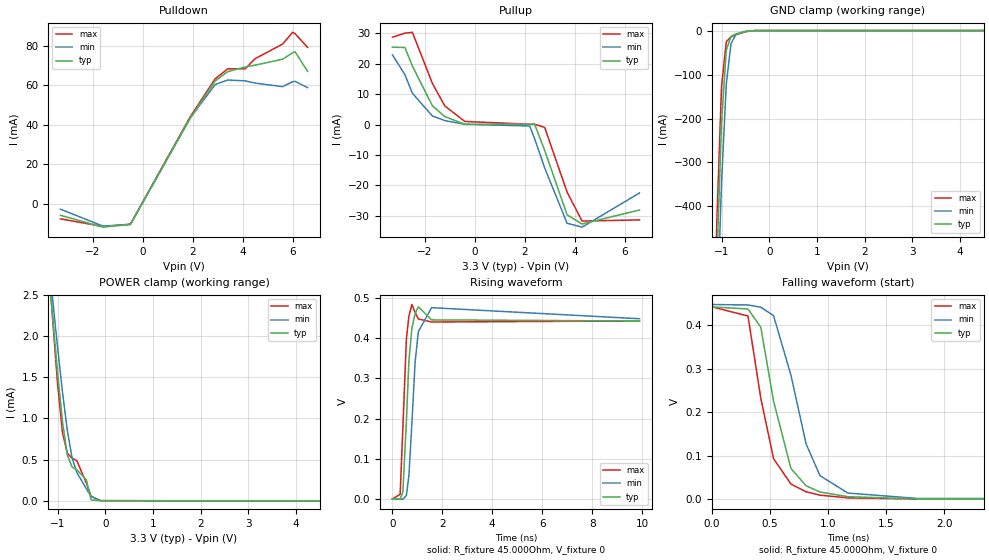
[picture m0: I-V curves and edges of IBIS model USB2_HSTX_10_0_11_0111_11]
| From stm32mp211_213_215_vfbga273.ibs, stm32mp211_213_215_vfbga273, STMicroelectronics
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[Model] USB2_HSTX_10_0_11_0111_11
Model_type   Output
Polarity   Non-Inverting
Enable   Active-High
C_comp   8.036pF   7.631pF   8.569pF
Vmeas = 200.000mV
Vref = 200.000mV
Rref = 45Ohms
Cref = 0pF
[Model Spec]
Vmeas   200.000mV   200.000mV   200.000mV
Vref   200.000mV   200.000mV   200.000mV
| This model is not intended for timing simulations.
| Warnings about Cref, Vref & Rref can be ignored
[Temperature Range]   25.000   125.000   -40.000
[Voltage Range]   3.300V   3.070V   3.630V
[GND Clamp Reference]   0.00V   0.00V   0.00V
[Pulldown Reference]   0.00V   0.00V   0.00V
[POWER Clamp Reference]   3.300V   3.070V   3.630V
[Pullup Reference]   3.300V   3.070V   3.630V
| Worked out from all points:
|   slope of the pulldown table from 0 to 0.495 V, typ, clamps not added: 42.6 ohm
|   GND clamp passes 1 mA (typ) near -0.43 V on its own axis
|   POWER clamp passes 1 mA (typ) near -0.91 V on its own axis
|   rising waveform, R_fixture 45.000Ohm, V_fixture 0: 20-80 % time 177ps typ, 237ps min, 137ps max; typ from 0 V to 0.442 V
|   falling waveform, R_fixture 45.000Ohm, V_fixture 0: 20-80 % time 196ps typ, 242ps min, 176ps max; typ from 0.442 V to 0 V
[GND Clamp]
-3.3V     -11.02A    -10.62A    -11.32A
-1.2V     -931.6mA   -1.049A    -855.7mA
-1.1V     -533.1mA   -671.7mA   -440.2mA
-1V       -209.4mA   -347mA     -127.3mA
-900mV    -44.44mA   -121.7mA   -25.6mA
-800mV    -13.15mA   -29.48mA   -14.15mA
-700mV    -7.742mA   -9.125mA   -9.769mA
-500mV    -2.127mA   -1.981mA   -2.894mA
-300mV    -19.29uA   -62.22uA   -13.76uA
6.6V      10.37uA    26.58uA    21.05uA
[Power Clamp]
-3.3V     3.206A     2.175A     4.855A
-1.2V     2.88mA     3.008mA    2.969mA
-1.1V     2.195mA    2.419mA    2.156mA
-1V       1.545mA    1.852mA    1.406mA
-900mV    967.9uA    1.325mA    831.4uA
-800mV    558.5uA    864.5uA    580.3uA
-700mV    412uA      525.9uA    517uA
-600mV    376.6uA    345uA      488.5uA
-400mV    254.2uA    146.6uA    216.8uA
-300mV    11.21uA    52.88uA    53.51uA
-100mV    94.92nA    985.3nA    361.1nA
6.6V      -3.569uA   -5.179uA   -2.984uA
[Pulldown]
-3.3V     -5.671mA   -2.581mA   -7.449mA
-1.6V     -11.64mA   -11.09mA   -11.31mA
-500mV    -10.25mA   -10.32mA   -10.1mA
1.9V      43.42mA    43.46mA    44.13mA
2.9V      62.15mA    60.37mA    63.26mA
3.4V      66.87mA    62.63mA    68.29mA
4.1V      69.19mA    62.19mA    68.26mA
4.5V      70.11mA    61.06mA    73.4mA
5.6V      73.12mA    59.29mA    80.76mA
6V        76.33mA    61.76mA    86.69mA
6.1V      76.87mA    61.94mA    85.99mA
6.6V      66.99mA    58.79mA    79.1mA
[Pullup]
-3.3V     25.41mA    22.88mA    28.68mA
-2.8V     25.3mA     16.38mA    30mA
-2.5V     19.22mA    10.28mA    30.28mA
-1.7V     6.185mA    2.829mA    13.54mA
-1.2V     2.602mA    1.31mA     6.111mA
-400mV    111.7uA    77.66uA    1.021mA
2.2V      68.59uA    -465.1uA   104.8uA
2.4V      56.18uA    -4.685mA   90.82uA
2.8V      -8.459mA   -14.22mA   -920uA
3.7V      -29.65mA   -32.41mA   -22.19mA
4.3V      -32.64mA   -33.68mA   -31.68mA
6.6V      -28.04mA   -22.46mA   -31.3mA
[Ramp]
R_load=45.000Ohm
dV/dt_r   633.005mV/980.000ps  601.223mV/995.000ps  686.718mV/915.000ps
dV/dt_f   635.188mV/225.000ps  604.118mV/285.000ps  688.534mV/210.000ps
[Rising waveform]
R_fixture=45.000Ohm
V_fixture=0
0s        452.3nV    3.135uV    468.1nV
310ps     -557.4uV   -364.4uV   12.02mV
420ps     18.8mV     -644.1uV   179.9mV
560ps     193.8mV    8.956mV    398.1mV
660ps     342.6mV    57.92mV    454.4mV
780ps     424.4mV    188.7mV    483.5mV
910ps     461.2mV    340.9mV    463.7mV
1.04ns    477.7mV    416.3mV    447.5mV
1.57ns    445.3mV    475.6mV    440mV
9.9ns     442.4mV    448.1mV    442.6mV
[Falling waveform]
R_fixture=45.000Ohm
V_fixture=0
0s        441.9mV    447.5mV    442.1mV
310ps     437.2mV    446.4mV    421mV
420ps     395.5mV    441.3mV    232.7mV
530ps     225.9mV    422mV      93.46mV
680ps     70.69mV    285.1mV    34.97mV
810ps     31.17mV    127.6mV    17.35mV
930ps     16.79mV    54.32mV    9.567mV
1.17ns    6.065mV    14.44mV    3.331mV
1.77ns    897.4uV    2.036mV    703uV
9.9ns     14.42uV    31.18uV    4.706uV
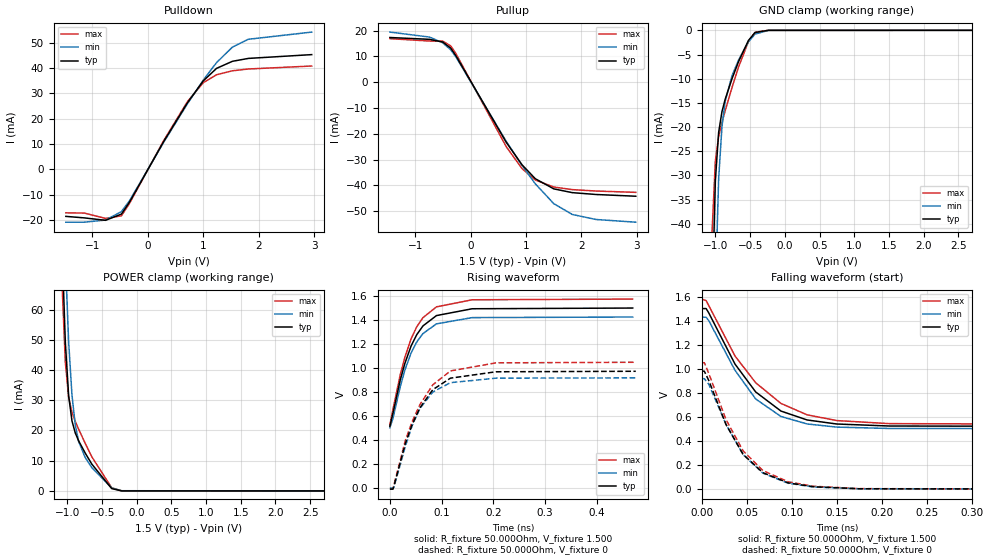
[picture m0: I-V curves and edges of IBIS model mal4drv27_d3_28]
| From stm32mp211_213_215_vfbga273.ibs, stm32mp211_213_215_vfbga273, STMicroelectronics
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[Model] mal4drv27_d3_28
Model_type   I/O
Polarity   Non-Inverting
Enable   Active-High
C_comp   1.653pF   1.649pF   1.658pF
C_comp_pullup   821.240fF   815.174fF   828.427fF
C_comp_pulldown 737.945fF   733.914fF   744.436fF
Vinh = 885.000mV
Vinl = 615.000mV
Vmeas = 750.000mV
Vref = 750.000mV
Rref = 50Ohms
Cref = 0pF
[Model Spec]
Vinh   885.000mV   848.000mV   923.000mV
Vinl   615.000mV   578.000mV   653.000mV
Vmeas   750.000mV   713.000mV   788.000mV
Vref   750.000mV   713.000mV   788.000mV
D_overshoot_ampl_h 0.4 NA   NA
D_overshoot_ampl_l 0.4 NA   NA
D_overshoot_area_l 100.000m NA   NA
D_overshoot_area_h 100.000m NA   NA
[Receiver Thresholds]
Vth = 750.000mV
Vth_min = 713.000mV
Vth_max = 788.000mV
Vinh_ac = 135.000mV
Vinh_dc = 100.000mV
Vinl_ac = -135.000mV
Vinl_dc = -100.000mV
Tslew_ac = 5.000ns
Threshold_sensitivity = 0.5
Reference_supply Pullup_ref
[Temperature Range]   25.000   125.000   -40.000
[Voltage Range]   1.500V   1.425V   1.575V
[GND Clamp Reference]   0.00V   0.00V   0.00V
[C Comp Corner]
| variable   typ   min   max
C_comp 1.658pF   1.653pF   1.649pF
C_comp_pullup 821.240fF   828.427fF   815.174fF
C_comp_pulldown 733.914fF   744.436fF   737.945fF
[Pulldown Reference]   0.00V   0.00V   0.00V
[POWER Clamp Reference]   1.500V   1.425V   1.575V
[Pullup Reference]   1.500V   1.425V   1.575V
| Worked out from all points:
|   slope of the pulldown table from 0 to 0.225 V, typ, clamps not added: 26 ohm
|   slope of the pullup table from 0 to 0.225 V, typ, clamps not added: 26.5 ohm
|   GND clamp passes 1 mA (typ) near -0.47 V on its own axis
|   POWER clamp passes 1 mA (typ) near -0.37 V on its own axis
|   rising waveform, R_fixture 50.000Ohm, V_fixture 1.500: 20-80 % time 45.5ps typ, 43.8ps min, 45.4ps max; typ from 0.513 V to 1.5 V
|   rising waveform, R_fixture 50.000Ohm, V_fixture 0: 20-80 % time 56ps typ, 49ps min, 60.9ps max; typ from -0.013 V to 0.972 V
|   falling waveform, R_fixture 50.000Ohm, V_fixture 1.500: 20-80 % time 54.5ps typ, 49.6ps min, 62.5ps max; typ from 1.5 V to 0.521 V
|   falling waveform, R_fixture 50.000Ohm, V_fixture 0: 20-80 % time 43.5ps typ, 42.5ps min, 45.2ps max; typ from 0.981 V to 0 V
[GND Clamp]
-1.48V    -1.356A    -1.372A    -1.368A
-1.05V    -57.52mA   -98.82mA   -41.99mA
-1.002V   -31.12mA   -53.93mA   -27.05mA
-954.6mV  -21.13mA   -30.8mA    -21.99mA
-906.8mV  -16.83mA   -19.93mA   -19.06mA
-859.1mV  -14.2mA    -14.62mA   -16.56mA
-763.6mV  -10.09mA   -9.457mA   -11.91mA
-668.2mV  -6.482mA   -6.16mA    -7.611mA
-525mV    -2.097mA   -2.366mA   -2.333mA
-429.5mV  -449.8uA   -771.1uA   -394uA
-238.6mV  -1.709uA   -14.74uA   -370nA
2.959V    53.06nA    707.1nA    76.78nA
[Power Clamp]
-1.459V   570.2mA    591.8mA    567.2mA
-1.077V   80.71mA    114.2mA    68.27mA
-1.03V    49.21mA    76.71mA    42.66mA
-981.8mV  31.4mA     49.26mA    30.9mA
-934.1mV  23.16mA    31.72mA    25.95mA
-886.4mV  19.16mA    21.79mA    22.98mA
-838.6mV  16.6mA     16.39mA    20.46mA
-743.2mV  12.52mA    11.03mA    15.74mA
-647.7mV  8.857mA    7.696mA    11.27mA
-361.4mV  773.2uA    986uA      1.034mA
-218.2mV  12.39uA    63.5uA     9.952uA
2.98V     -55.08nA   -1.144uA   -55.82nA
[Pulldown]
-1.48V    -18.6mA    -20.9mA    -17.2mA
-1.145V   -19.2mA    -20.9mA    -17.3mA
-763.6mV  -20.16mA   -20.06mA   -19.41mA
-477.3mV  -17.72mA   -16.73mA   -18.39mA
-334.1mV  -13.11mA   -12.56mA   -13.62mA
286.4mV   10.96mA    10.65mA    11.33mA
715.9mV   26.29mA    25.91mA    26.75mA
1.002V    34.94mA    35.26mA    34.24mA
1.241V    39.87mA    42.14mA    37.35mA
1.527V    42.66mA    48.26mA    38.91mA
1.814V    43.8mA     51.36mA    39.62mA
2.959V    45.3mA     54.2mA     40.8mA
[Pullup]
-1.459V   17.3mA     19.4mA     16.86mA
-743.2mV  16.59mA    17.47mA    15.93mA
-504.6mV  15.55mA    15.25mA    15.9mA
-361.4mV  13.21mA    12.54mA    14.08mA
-265.9mV  10.19mA    9.733mA    11.02mA
640.9mV   -23.29mA   -22.91mA   -24.99mA
927.3mV   -32.04mA   -32.32mA   -33.51mA
1.166V    -37.41mA   -39.38mA   -37.92mA
1.5V      -41.35mA   -47.08mA   -40.64mA
1.834V    -42.81mA   -51.27mA   -41.64mA
2.264V    -43.53mA   -53.22mA   -42.19mA
2.98V     -44.2mA    -54.26mA   -42.7mA
[Ramp]
R_load=50.000Ohm
dV/dt_r   585.090mV/51.500ps  551.819mV/47.000ps  624.990mV/54.000ps
dV/dt_f   585.090mV/50.000ps  551.819mV/47.000ps  624.990mV/55.000ps
[Rising waveform]
R_fixture=50.000Ohm
V_fixture=1.500
V_fixture_min=1.425
V_fixture_max=1.575
0s        512.6mV    499.1mV    523.9mV
6ps       621.6mV    578mV      654.3mV
20ps      897.6mV    841mV      941.6mV
29ps      1.038V     982.2mV    1.089V
41ps      1.183V     1.125V     1.243V
52ps      1.278V     1.217V     1.344V
64ps      1.351V     1.287V     1.42V
90ps      1.437V     1.368V     1.51V
159ps     1.494V     1.42V      1.569V
469ps     1.5V       1.425V     1.575V
[Rising waveform]
R_fixture=50.000Ohm
V_fixture=0
0s        -13.22mV   -4.701mV   -7.609mV
6ps       -13.22mV   -4.701mV   -7.609mV
8ps       15.04mV    5.879mV    25.27mV
30ps      369.4mV    345.7mV    395.1mV
43ps      526.2mV    517.1mV    550.7mV
58ps      666mV      660mV      693.2mV
83ps      818.3mV    798.6mV    858.8mV
117ps     914.2mV    876.6mV    974.5mV
205ps     967.5mV    914.2mV    1.042V
475ps     971.7mV    916.7mV    1.047V
[Falling waveform]
R_fixture=50.000Ohm
V_fixture=1.500
V_fixture_min=1.425
V_fixture_max=1.575
0s        1.501V     1.429V     1.58V
5ps       1.501V     1.429V     1.567V
8ps       1.464V     1.4V       1.525V
37ps      1.04V      988.5mV    1.107V
60ps      807.7mV    749.2mV    884.4mV
88ps      649.1mV    604.1mV    712.5mV
117ps     575.2mV    542mV      617.9mV
150ps     541.5mV    515.8mV    570mV
208ps     524.9mV    504.4mV    544.7mV
474ps     521.4mV    502.3mV    538.7mV
[Falling waveform]
R_fixture=50.000Ohm
V_fixture=0
0s        980.7mV    918.2mV    1.051V
3ps       980.7mV    918.2mV    1.051V
8ps       902.3mV    871.3mV    960.9mV
27ps      537.9mV    540mV      579.2mV
46ps      289.4mV    287.1mV    318.7mV
68ps      136.8mV    133mV      154.4mV
96ps      52.35mV    49.03mV    61.06mV
124ps     20.03mV    18.04mV    24.06mV
175ps     3.445mV    3.002mV    4.366mV
472ps     2.087uV    7.008uV    2.036uV
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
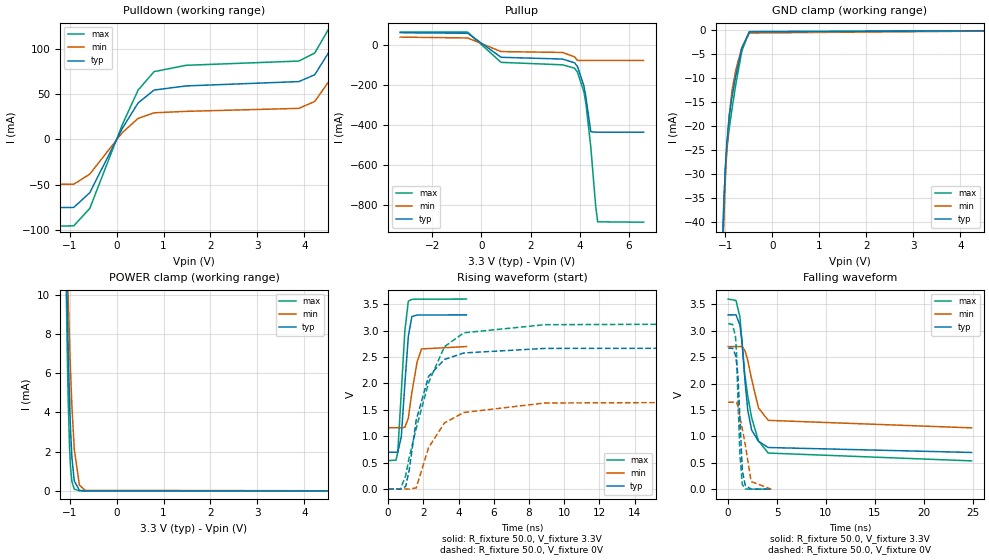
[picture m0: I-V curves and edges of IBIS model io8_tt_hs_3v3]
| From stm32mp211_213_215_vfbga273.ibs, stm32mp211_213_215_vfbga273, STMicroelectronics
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[Model]   io8_tt_hs_3v3
Model_type I/O
Polarity   Non-Inverting
Enable   Active-Low
| CAP_THRESHOLD on pad IOTT is "UDTCAPC" :
| Rising=30.0% of vddiov33m   Falling=70.0% of vddiov33m
| C_comp min and max val. don't necessarily correlate with the min and max pvt
| but are the smallest and greatest pad capacitance found.
| var   typ   min   max
C_comp   1.01876pF  1.01072pF  1.02145pF
|C_comp_pullup   495.66000fF  479.35500fF  510.70500fF
|C_comp_pulldown   523.10000fF  531.36929fF  510.74000fF
Vinl = 1.35V
Vinh = 1.8V
Vmeas = 1.65V   | Reference voltage for timing measurements
Cref  = 50.0pF   | Timing specification test load capacitance value
Rref  = 1.0MOhm   | Timing specification test load resistance value
Vref  = 1.815V   | Timing specification test load voltage
[Model Spec]
| TIME_THRESHOLD on pin ZIV08M is "CMOS" :
| Rising=50.0% of vddv08m   Falling=50.0% of vddv08m
Vinl 1.08570V 868.70000mV 1.21270V
Vinh 1.55630V 1.26230V 1.70930V
| variable   typ   min   max
[Temperature Range] 25.0 125.0 -40.0
| variable   typ   min   max
[Voltage Range] 3.3V 2.7V 3.6V
| variable   typ   min   max
[POWER Clamp Reference] 3.3V 2.7V 3.6V
| variable   typ   min   max
[GND Clamp Reference] 0V 0V 0V
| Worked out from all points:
|   slope of the pulldown table from 0 to 0.495 V, typ, clamps not added: 11.6 ohm
|   slope of the pullup table from 0 to 0.495 V, typ, clamps not added: 10.9 ohm
|   GND clamp passes 1 mA (typ) near -0.55 V on its own axis
|   POWER clamp passes 1 mA (typ) near -0.92 V on its own axis
|   rising waveform, R_fixture 50.0, V_fixture 3.3V: 20-80 % time 324ps typ, 432ps min, 308ps max; typ from 0.695 V to 3.3 V
|   falling waveform, R_fixture 50.0, V_fixture 3.3V: 20-80 % time 837ps typ, 1.2ns min, 1.33ns max; typ from 3.3 V to 0.695 V
|   rising waveform, R_fixture 50.0, V_fixture 0V: 20-80 % time 1.04ns typ, 1.55ns min, 1.64ns max; typ from 0 V to 2.67 V
|   falling waveform, R_fixture 50.0, V_fixture 0V: 20-80 % time 373ps typ, 836ps min, 339ps max; typ from 2.67 V to 0 V
[POWER Clamp]
-3.3V     1.353A     318.4mA    2.015A
-1.07V    12.07mA    13.62mA    10.38mA
-1.06V    10.79mA    12.68mA    8.745mA
-1.05V    9.571mA    11.76mA    7.253mA
-1.03V    7.341mA    9.999mA    4.748mA
-1V       4.588mA    7.595mA    2.215mA
-980mV    3.183mA    6.171mA    1.238mA
-950mV    1.704mA    4.337mA    481.8uA
-900mV    515.5uA    2.141mA    93.34uA
-790mV    29.45uA    301.7uA    4.884uA
-670mV    1.871uA    28.97uA    2.19uA
6.6V      0A         0A         0A
[GND Clamp]
-3.3V     -3.772A    -3.743A    -3.788A
-1.05V    -42.34mA   -45.44mA   -41.2mA
-1.04V    -38.9mA    -42mA      -37.88mA
-1.03V    -35.84mA   -38.88mA   -35.06mA
-1V       -28.57mA   -31.07mA   -28.88mA
-970mV    -23.48mA   -25.09mA   -24.97mA
-920mV    -18.07mA   -17.99mA   -20.63mA
-860mV    -13.91mA   -12.68mA   -16.46mA
-780mV    -9.536mA   -8.318mA   -11.38mA
-650mV    -3.744mA   -3.567mA   -4.327mA
-490mV    -324.2uA   -555.2uA   -259.7uA
6.6V      214nA      4.276uA    223.3nA
| variable   typ   min   max
[Pullup Reference] 3.3V 2.7V 3.6V
| variable   typ   min   max
[Pulldown Reference] 0V 0V 0V
[Pullup]
-3.3V     63.52mA    41.46mA    66.64mA
-560mV    60.73mA    37.23mA    66.64mA
800mV     -59.67mA   -31.11mA   -85.07mA
3.3V      -68.5mA    -35.37mA   -97.42mA
3.79V     -87.42mA   -57.42mA   -114.2mA
3.91V     -106.3mA   -75.62mA   -134.5mA
4.17V     -203.5mA   -75.62mA   -232.9mA
4.25V     -258.5mA   -75.62mA   -290.9mA
4.45V     -432.8mA   -75.62mA   -509.3mA
4.65V     -435.1mA   -75.62mA   -808.5mA
4.73V     -435.1mA   -75.62mA   -884.5mA
6.6V      -435.1mA   -75.62mA   -886.3mA
[Pulldown]
-3.3V     -76.59mA   -50.19mA   -97.29mA
-910mV    -75.37mA   -49.66mA   -95.8mA
-570mV    -59.08mA   -38.48mA   -76.52mA
120mV     12mA       7.376mA    15.98mA
460mV     40.46mA    23.32mA    54.73mA
800mV     54.75mA    29.51mA    75.15mA
1.48V     59.3mA     31.12mA    82.16mA
3.88V     64.12mA    34.44mA    86.87mA
4.22V     71.69mA    42.06mA    95.8mA
4.56V     100mA      67.27mA    126.4mA
4.9V      185.2mA    140.4mA    220.4mA
6.6V      1.447A     1.603A     1.41A
[Ramp]
dV/dt_r 1.60177V/1.0384ns 987.98612mV/1.54817ns 1.87951V/1.63945ns
dV/dt_f 1.56279V/831.68027ps 923.47072mV/1.19753ns 1.83839V/1.32708ns
R_load = 50.0
| Removed startup time: 0s 0s 0s  .
| Removed end time: 4.45ns.
[Rising Waveform]
R_fixture   = 50.0
V_fixture   = 3.3V
V_fixture_min = 2.7V
V_fixture_max = 3.6V
0s        695.3mV    1.161V     536mV
450ps     695.2mV    1.161V     545.3mV
550ps     693.5mV    1.161V     691.7mV
750ps     985.9mV    1.161V     1.826V
950ps     1.975V     1.168V     2.986V
1.15ns    2.89V      1.341V     3.56V
1.35ns    3.269V     1.828V     3.594V
1.65ns    3.297V     2.408V     3.598V
1.9ns     3.298V     2.654V     3.598V
4.45ns    3.3V       2.7V       3.6V
| Removed startup time: 0s 0s 0s  .
| Removed end time: 24.9ns.
[Falling Waveform]
R_fixture   = 50.0
V_fixture   = 3.3V
V_fixture_min = 2.7V
V_fixture_max = 3.6V
0s        3.3V       2.7V       3.6V
800ps     3.302V     2.7V       3.573V
1.2ns     3.109V     2.702V     3.266V
1.4ns     2.826V     2.701V     2.821V
1.7ns     2.1V       2.633V     2.171V
2ns       1.503V     2.445V     1.77V
2.4ns     1.122V     2.083V     1.355V
3.1ns     906.9mV    1.54V      913.4mV
4.1ns     788.9mV    1.303V     684mV
24.9ns    695.3mV    1.161V     536mV
| Removed startup time: 0s 0s 0s  .
| Removed end time: 24.9ns.
[Rising Waveform]
R_fixture   = 50.0
V_fixture   = 0V
V_fixture_min = 0V
V_fixture_max = 0V
0s        255.5nV    1.563uV    316nV
700ps     -5.265mV   -104uV     -1.081mV
1ns       45.66mV    -2.23mV    250.4mV
1.2ns     357.8mV    -4.136mV   596.6mV
1.6ns     1.31V      20.34mV    1.15V
2.3ns     2.133V     783.6mV    2.015V
3.2ns     2.455V     1.251V     2.697V
4.3ns     2.578V     1.449V     2.96V
8.9ns     2.664V     1.629V     3.114V
24.9ns    2.67V      1.647V     3.133V
| Removed startup time: 0s 0s 0s  .
| Removed end time: 4.4ns.
[Falling Waveform]
R_fixture   = 50.0
V_fixture   = 0V
V_fixture_min = 0V
V_fixture_max = 0V
0s        2.67V      1.647V     3.133V
450ps     2.67V      1.647V     3.12V
750ps     2.539V     1.647V     2.888V
850ps     2.411V     1.643V     2.6V
1ns       2.164V     1.58V      1.725V
1.2ns     1.354V     1.364V     657.5mV
1.45ns    348mV      1.137V     87.39mV
1.75ns    73.53mV    844.5mV    3.39mV
2.35ns    1.217mV    144.9mV    820.6uV
4.4ns     139.7uV    291.2uV    165.7uV
